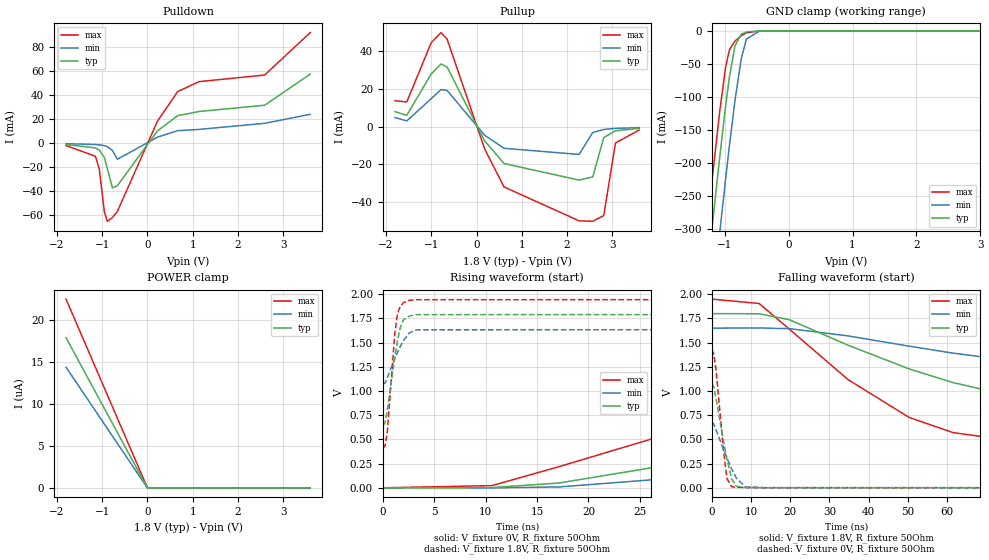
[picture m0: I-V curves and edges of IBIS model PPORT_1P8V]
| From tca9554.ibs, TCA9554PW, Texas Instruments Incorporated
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[Model]   PPORT_1P8V
Model_type   I/O
Polarity   Non-Inverting
Enable   Active-Low
Vinl = 0.495
Vinh = 1.365
Vmeas = 0.9
Vref = 1.8
Cref = 15pF
Rref = 50
|   typ   min   max
C_comp   2.533p   2.474p   2.695p
|C_comp (ON state)   2.684p   2.578p   2.839p
|C_comp (OFF state)   2.533p   2.474p   2.695p
[Voltage Range]   1.8   1.65   1.95
[Temperature Range]   27   125   -40
[Pullup Reference]   1.8   1.65   1.95
[Pulldown Reference]   -0   -0   -0
[Power Clamp Reference]   1.8   1.65   1.95
[GND Clamp Reference]   -0   -0   -0
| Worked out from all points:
|   slope of the pulldown table from 0 to 0.27 V, typ, clamps not added: 21.9 ohm
|   slope of the pullup table from 0 to 0.27 V, typ, clamps not added: 25.2 ohm
|   GND clamp passes 1 mA (typ) near -0.61 V on its own axis
|   falling waveform, V_fixture 1.8V, R_fixture 50Ohm: 20-80 % time 56.9ns typ, 73.5ns min, 31.3ns max; typ from 1.8 V to 0.647 V
|   rising waveform, V_fixture 0V, R_fixture 50Ohm: 20-80 % time 54.4ns typ, 64.8ns min, 33.8ns max; typ from 0 V to 1.08 V
|   rising waveform, V_fixture 1.8V, R_fixture 50Ohm: 20-80 % time 975ps typ, 1.45ns min, 660ps max; typ from 0.647 V to 1.8 V
|   falling waveform, V_fixture 0V, R_fixture 50Ohm: 20-80 % time 2.95ns typ, 4.16ns min, 1.96ns max; typ from 1.08 V to 0 V
[Pulldown]
|   Voltage   I(typ)   I(min)   I(max)
-1.8V     -988.9uA   -319.7uA   -1.854mA
-1.152V   -3.801mA   -972.2uA   -10.75mA
-1.066V   -5.591mA   -1.262mA   -21.2mA
-952.2mV  -11.84mA   -1.964mA   -57.11mA
-887.4mV  -21.13mA   -2.728mA   -64.85mA
-774mV    -37.11mA   -5.939mA   -61.69mA
-666mV    -35.22mA   -13.27mA   -56.62mA
219.6mV   10.33mA    5.124mA    18.35mA
667.8mV   23.04mA    10.53mA    43.07mA
1.138V    26.48mA    11.57mA    51.3mA
2.59V     31.69mA    16.66mA    56.82mA
3.595V    57.58mA    24.11mA    92.12mA
[GND Clamp]
|   Voltage   I(typ)   I(min)   I(max)
-1.8V     -871.9mA   -986.3mA   -800.7mA
-1.444V   -528.9mA   -644.8mA   -456.5mA
-1.228V   -326.2mA   -442.1mA   -253.8mA
-1.19V    -291.5mA   -407.3mA   -219.4mA
-1.076V   -190.2mA   -304.3mA   -121.1mA
-984.6mV  -113.5mA   -223.6mA   -54.6mA
-925.2mV  -69.39mA   -173.4mA   -28.76mA
-838.8mV  -22.85mA   -105.4mA   -15.44mA
-741.6mV  -5.182mA   -42.86mA   -7.612mA
-660.6mV  -1.822mA   -12.47mA   -3.153mA
-450mV    -61.54uA   -121.3uA   -76.79uA
3.595V    0A         0A         0A
[Pullup]
|   Voltage   I(typ)   I(min)   I(max)
-1.8V     7.964mA    4.868mA    13.79mA
-1.541V   6.073mA    3.062mA    13.14mA
-1.001V   28mA       14.88mA    44.56mA
-784.8mV  33.29mA    19.7mA     49.96mA
-649.8mV  31.68mA    19.26mA    46.48mA
181.8mV   -7.607mA   -4.572mA   -11.92mA
608.4mV   -19.53mA   -11.46mA   -31.97mA
2.266V    -28.34mA   -14.71mA   -49.94mA
2.569V    -26.62mA   -3.061mA   -50.2mA
2.812V    -5.75mA    -1.441mA   -47.11mA
3.071V    -2.144mA   -898uA     -8.613mA
3.595V    -898.7uA   -502.8uA   -1.763mA
[POWER Clamp]
|   Voltage   I(typ)   I(min)   I(max)
-1.8V     17.93uA    14.41uA    22.54uA
-7.2mV    42.51nA    30.38nA    61.3nA
3.6mV     0A         0A         0A
3.595V    0A         0A         0A
[Ramp]
R_load = 50
|   typ   min   max
dV/dt_r   0.647397/5.41754e-08   0.404813/6.47919e-08   0.85926/3.37788e-08
dV/dt_f   0.691936/5.67855e-08   0.344985/7.34457e-08   0.925583/3.12715e-08
[Falling Waveform]
V_fixture = 1.8V
V_fixture_min = 1.65V
V_fixture_max = 1.95V
R_fixture = 50Ohm
C_fixture = 0F
|   Time   V(typ)   V(min)   V(max)
0s        1.8V       1.65V      1.95V
12.05ns   1.799V     1.652V     1.905V
19.79ns   1.737V     1.645V     1.639V
34.76ns   1.474V     1.57V      1.118V
50.34ns   1.229V     1.464V     727.6mV
61.52ns   1.088V     1.392V     571.2mV
78.25ns   932.2mV    1.305V     477.1mV
109.2ns   770.1mV    1.2V       426.1mV
168.6ns   671.9mV    1.113V     409.6mV
499.9ns   646.8mV    1.075V     407.4mV
[Rising Waveform]
V_fixture = 0V
V_fixture_min = 0V
V_fixture_max = 0V
R_fixture = 50Ohm
C_fixture = 0F
|   Time   V(typ)   V(min)   V(max)
0s        927.9pV    45.09nV    198.9uV
10.62ns   2.294mV    -339.3uV   22.91mV
17.16ns   50.23mV    9.359mV    219.5mV
34.76ns   358.3mV    152.9mV    779mV
50.34ns   586.1mV    291.3mV    1.108V
66.41ns   757.5mV    403.3mV    1.29V
85.73ns   889.5mV    497.7mV    1.374V
119.1ns   1.006V     591.1mV    1.417V
168.6ns   1.061V     647mV      1.429V
499.9ns   1.079V     674.7mV    1.432V
[Rising Waveform]
V_fixture = 1.8V
V_fixture_min = 1.65V
V_fixture_max = 1.95V
R_fixture = 50Ohm
C_fixture = 0F
|   Time   V(typ)   V(min)   V(max)
0s        646.8mV    1.075V     407.4mV
202ps     668.9mV    1.08V      431.8mV
432ps     801.4mV    1.137V     576.4mV
1.16ns    1.348V     1.334V     1.589V
1.428ns   1.521V     1.4V       1.802V
1.707ns   1.661V     1.463V     1.877V
1.996ns   1.735V     1.519V     1.913V
2.574ns   1.775V     1.6V       1.938V
3.265ns   1.79V      1.633V     1.944V
499.9ns   1.8V       1.65V      1.95V
[Falling Waveform]
|Gnd
V_fixture = 0V
V_fixture_min = 0V
V_fixture_max = 0V
R_fixture = 50Ohm
C_fixture = 0F
|   Time   V(typ)   V(min)   V(max)
0s        1.079V     674.7mV    1.432V
432ps     1.049V     664.5mV    1.393V
1.044ns   926.7mV    600.8mV    1.229V
2.965ns   487.5mV    396.8mV    388.1mV
3.843ns   299.1mV    307.3mV    97.17mV
5.053ns   94.51mV    194.6mV    11.74mV
6.281ns   14.91mV    98.89mV    6.123mV
8.566ns   4.312mV    9.939mV    3.006mV
13.58ns   1.254mV    1.938mV    1.737mV
499.9ns   23.07nV    52.65nV    198.9uV
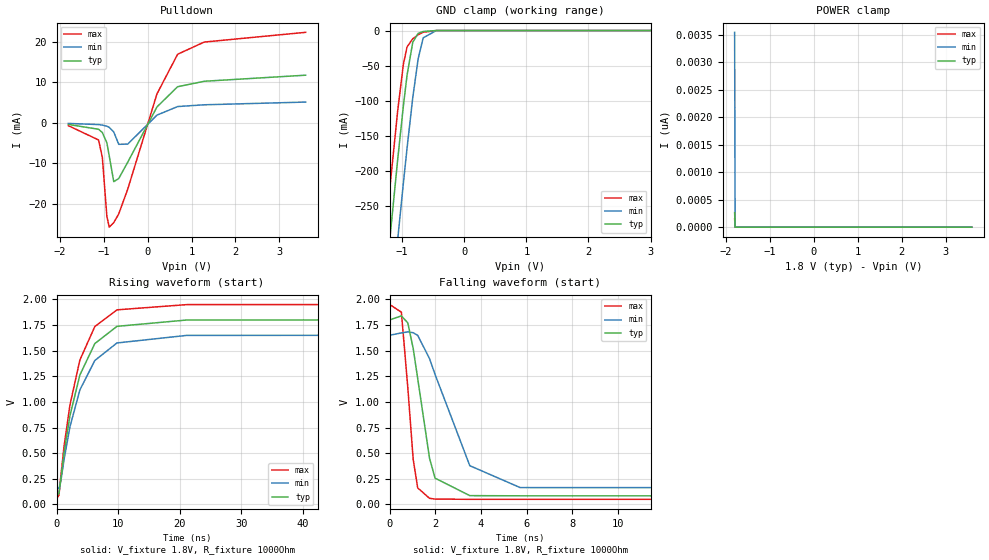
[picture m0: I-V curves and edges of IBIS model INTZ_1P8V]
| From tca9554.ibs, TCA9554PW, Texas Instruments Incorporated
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[Model]   INTZ_1P8V
Model_type   Open_drain
Polarity   Non-Inverting
Vmeas = 0.9
Vref = 1.8
Cref = 15pF
Rref = 1000
|   typ   min   max
|   (nom PVT)   (slow PVT)   (fast PVT)
C_comp   1.655p   1.530p   1.689p
|C_comp (ON state)   1.655p   1.530p   1.689p
|C_comp (OFF state)   1.584p   1.517p   1.716p
| Where   nom PVT is  Nominal Process, 1.8V, 27C
|   Fast PVT is Strong Process, 1.95V, -40C
|   Slow PVT is Weak Process, 1.65V, 125C
[Voltage Range]   1.8   1.65   1.95
[Temperature Range]   27   125   -40
[Pullup Reference]   1.8   1.65   1.95
[Pulldown Reference]   -0   -0   -0
[Power Clamp Reference]   1.8   1.65   1.95
[GND Clamp Reference]   -0   -0   -0
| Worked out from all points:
|   slope of the pulldown table from 0 to 0.27 V, typ, clamps not added: 56.2 ohm
|   GND clamp passes 1 mA (typ) near -0.63 V on its own axis
|   falling waveform, V_fixture 1.8V, R_fixture 1000Ohm: 20-80 % time 697ps typ, 1.47ns min, 385ps max; typ from 1.8 V to 0.085 V
|   rising waveform, V_fixture 1.8V, R_fixture 1000Ohm: 20-80 % time 4.03ns typ, 4.34ns min, 3.79ns max; typ from 0.085 V to 1.8 V
[Pulldown]
|   Voltage   I(typ)   I(min)   I(max)
-1.8V     -366.9uA   -119.8uA   -673.5uA
-1.114V   -1.557mA   -398.7uA   -4.198mA
-1.028V   -2.36mA    -527.3uA   -8.479mA
-925.2mV  -4.899mA   -808.9uA   -23.02mA
-871.2mV  -8.149mA   -1.078mA   -25.72mA
-768.6mV  -14.48mA   -2.215mA   -24.59mA
-655.2mV  -13.72mA   -5.277mA   -22.45mA
-450mV    -9.679mA   -5.218mA   -16.33mA
214.2mV   3.955mA    1.936mA    7.171mA
684mV     8.943mA    4.047mA    16.96mA
1.289V    10.29mA    4.483mA    19.97mA
3.595V    11.79mA    5.155mA    22.37mA
[GND Clamp]
|   Voltage   I(typ)   I(min)   I(max)
-1.8V     -871.5mA   -985.9mA   -800.3mA
-1.444V   -528.4mA   -644.2mA   -455.8mA
-1.222V   -320.4mA   -436.4mA   -247.8mA
-1.184V   -285.7mA   -401.5mA   -213.4mA
-1.071V   -184.3mA   -298.5mA   -114.8mA
-979.2mV  -107.6mA   -217.7mA   -48.24mA
-919.8mV  -63.58mA   -167.6mA   -23.38mA
-828mV    -16.75mA   -95.69mA   -11.69mA
-741.6mV  -4.067mA   -40.48mA   -6.075mA
-660.6mV  -1.392mA   -10.45mA   -2.456mA
-450mV    -29.51uA   -72.57uA   -35.78uA
3.595V    0A         0A         0A
[POWER Clamp]
|   Voltage   I(typ)   I(min)   I(max)
-1.8V     265.2pA    3.548nA    149.6pA
-1.789V   0A         0A         0A
-1.784V   0A         0A         0A
3.595V    0A         0A         0A
[Ramp]
R_load = 1000
|   typ   min   max
dV/dt_r   1.0292/4.03357e-09   0.895551/4.33649e-09   1.1398/3.78691e-09
dV/dt_f   1.0292/6.96978e-10   0.895551/1.46926e-09   1.1398/3.85397e-10
[Falling Waveform]
V_fixture = 1.8V
V_fixture_min = 1.65V
V_fixture_max = 1.95V
R_fixture = 1000Ohm
C_fixture = 0F
|   Time   V(typ)   V(min)   V(max)
0s        1.8V       1.65V      1.95V
513.5ps   1.839V     1.673V     1.875V
795.2ps   1.771V     1.683V     1.141V
1.031ns   1.522V     1.675V     440.1mV
1.229ns   1.228V     1.649V     161.7mV
1.747ns   451.3mV    1.422V     60.15mV
1.99ns    256.7mV    1.268V     52.88mV
3.511ns   86.36mV    378.3mV    50.34mV
5.717ns   84.64mV    165mV      50.45mV
99.9ns    84.66mV    157.4mV    50.33mV
[Rising Waveform]
V_fixture = 1.8V
V_fixture_min = 1.65V
V_fixture_max = 1.95V
R_fixture = 1000Ohm
C_fixture = 0F
|   Time   V(typ)   V(min)   V(max)
0s        84.66mV    157.4mV    50.33mV
392.7ps   107.9mV    158.9mV    90.98mV
674.3ps   232.6mV    218.6mV    263.9mV
1.229ns   506.2mV    439.9mV    569.9mV
2.18ns    866.2mV    758.2mV    970.3mV
3.793ns   1.263V     1.117V     1.409V
6.22ns    1.569V     1.404V     1.735V
9.815ns   1.737V     1.575V     1.898V
21.19ns   1.799V     1.649V     1.949V
99.9ns    1.8V       1.65V      1.95V
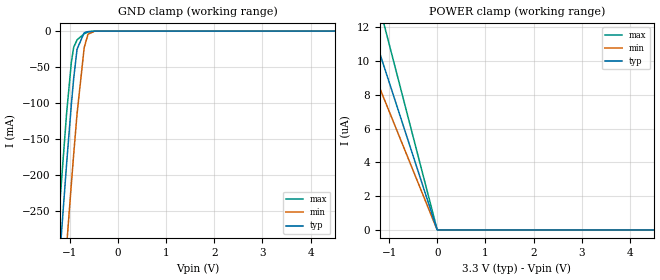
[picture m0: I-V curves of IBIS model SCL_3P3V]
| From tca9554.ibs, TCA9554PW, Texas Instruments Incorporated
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[Model]   SCL_3P3V
Model_type   Input
Vinl = .8
Vinh = 2
|   typ   min   max
|   (nom PVT)   (slow PVT)   (fast PVT)
C_comp   1.364p   1.306p   1.458p
| Where   nom PVT is  Nominal Process, 3.3V, 27C
|   Fast PVT is Strong Process, 3.6V, -40C
|   Slow PVT is Weak Process, 3.0V, 125C
[Voltage Range]   3.3   3   3.6
[Temperature Range]   27   125   -40
[Power Clamp Reference]   3.3   3   3.6
[GND Clamp Reference]   -0   -0   -0
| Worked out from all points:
|   GND clamp passes 1 mA (typ) near -0.65 V on its own axis
[GND Clamp]
|   Voltage   I(typ)   I(min)   I(max)
-3.3V     -2.345A    -2.454A    -2.279A
-1.32V    -411mA     -527.2mA   -338.2mA
-1.27V    -364.7mA   -480.9mA   -291.9mA
-1.201V   -300.6mA   -416.5mA   -228mA
-1.073V   -184.9mA   -299.3mA   -115mA
-973.5mV  -102.1mA   -212.2mA   -43.17mA
-924mV    -65.27mA   -170.3mA   -22.32mA
-854.7mV  -25.09mA   -114.7mA   -12.22mA
-706.2mV  -2.209mA   -22.91mA   -3.725mA
-627mV    -734.8uA   -4.35mA    -1.288mA
-488.4mV  -61.56uA   -151uA     -81.68uA
6.59V     0A         0A         0A
[POWER Clamp]
|   Voltage   I(typ)   I(min)   I(max)
-3.3V     28.92uA    23.24uA    36.36uA
-1.914V   16.75uA    13.45uA    21.07uA
-1.567V   13.71uA    11.01uA    17.25uA
-1.449V   12.67uA    10.18uA    15.94uA
-1.211V   10.59uA    8.503uA    13.32uA
-825mV    7.205uA    5.785uA    9.067uA
-13.2mV   91.45nA    69.92nA    122.4nA
-3.3mV    4.698nA    46.61nA    13.27nA
16.5mV    0A         0A         0A
6.59V     0A         0A         0A
